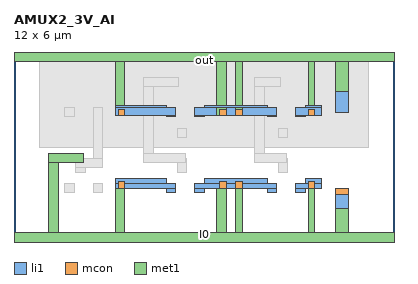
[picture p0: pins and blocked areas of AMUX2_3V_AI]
MACRO AMUX2_3V_AI
  CLASS CORE ;
  FOREIGN AMUX2_3V_AI ;
  ORIGIN 0.000 0.000 ;
  SIZE 12.000 BY 6.000 ;
  SITE unithddbl ;
  PIN I0
    DIRECTION INPUT ;
    USE SIGNAL ;
    ANTENNADIFFAREA 1.210000 ;
    PORT
      LAYER li1 ;
        RECT 3.200 1.850 4.800 2.000 ;
        RECT 6.000 1.850 8.000 2.000 ;
        RECT 9.200 1.850 9.700 2.000 ;
        RECT 3.200 1.700 5.100 1.850 ;
        RECT 4.800 1.550 5.100 1.700 ;
        RECT 5.700 1.700 8.300 1.850 ;
        RECT 5.700 1.550 6.000 1.700 ;
        RECT 8.000 1.550 8.300 1.700 ;
        RECT 8.900 1.700 9.700 1.850 ;
        RECT 8.900 1.550 9.200 1.700 ;
        RECT 10.150 1.050 10.550 1.700 ;
      LAYER mcon ;
        RECT 3.300 1.700 3.500 1.900 ;
        RECT 6.500 1.700 6.700 1.900 ;
        RECT 7.000 1.700 7.200 1.900 ;
        RECT 9.300 1.700 9.500 1.900 ;
        RECT 10.150 1.500 10.550 1.700 ;
      LAYER met1 ;
        RECT 1.100 2.500 2.200 2.800 ;
        RECT 1.100 0.300 1.400 2.500 ;
        RECT 3.200 0.300 3.500 1.900 ;
        RECT 6.400 0.300 6.700 1.900 ;
        RECT 7.000 0.300 7.200 1.900 ;
        RECT 9.300 0.300 9.500 1.900 ;
        RECT 10.150 0.300 10.550 1.700 ;
        RECT 0.000 0.000 12.000 0.300 ;
    END
  END I0
  PIN out
    DIRECTION OUTPUT ;
    USE SIGNAL ;
    ANTENNADIFFAREA 1.210000 ;
    PORT
      LAYER li1 ;
        RECT 3.200 4.250 4.800 4.300 ;
        RECT 6.000 4.250 8.000 4.300 ;
        RECT 9.200 4.250 9.700 4.300 ;
        RECT 3.200 4.000 5.100 4.250 ;
        RECT 4.800 3.950 5.100 4.000 ;
        RECT 5.700 4.000 8.300 4.250 ;
        RECT 5.700 3.950 6.000 4.000 ;
        RECT 8.000 3.950 8.300 4.000 ;
        RECT 8.900 4.000 9.700 4.250 ;
        RECT 10.150 4.100 10.550 4.750 ;
        RECT 8.900 3.950 9.200 4.000 ;
      LAYER mcon ;
        RECT 3.300 4.000 3.500 4.200 ;
        RECT 6.500 4.000 6.700 4.200 ;
        RECT 7.000 4.000 7.200 4.200 ;
        RECT 9.300 4.000 9.500 4.200 ;
      LAYER met1 ;
        RECT 0.000 5.700 12.000 6.000 ;
        RECT 3.200 4.000 3.500 5.700 ;
        RECT 6.400 4.000 6.700 5.700 ;
        RECT 7.000 4.000 7.200 5.700 ;
        RECT 9.300 4.000 9.500 5.700 ;
        RECT 10.150 4.100 10.550 5.700 ;
    END
  END out
  OBS
      LAYER nwell ;
        RECT 0.800 3.000 11.200 5.700 ;
      LAYER li1 ;
        RECT 1.600 3.950 1.900 4.250 ;
        RECT 2.500 2.650 2.800 4.250 ;
        RECT 5.150 3.300 5.450 3.600 ;
        RECT 8.350 3.300 8.650 3.600 ;
        RECT 1.950 2.350 2.800 2.650 ;
        RECT 1.950 2.200 2.250 2.350 ;
        RECT 5.150 2.200 5.450 2.650 ;
        RECT 8.350 2.200 8.650 2.650 ;
        RECT 1.600 1.550 1.900 1.850 ;
        RECT 2.500 1.550 2.800 1.850 ;
      LAYER met1 ;
        RECT 4.100 4.900 5.200 5.200 ;
        RECT 7.600 4.900 8.400 5.200 ;
        RECT 4.100 2.800 4.400 4.900 ;
        RECT 7.600 2.800 7.900 4.900 ;
        RECT 4.100 2.500 5.400 2.800 ;
        RECT 7.600 2.500 8.600 2.800 ;
  END
END AMUX2_3V_AI
END LIBRARY

